VERSION 5.8 ;
BUSBITCHARS "[]" ;
DIVIDERCHAR "/" ;
UNITS
    DATABASE MICRONS 1000 ;
END UNITS

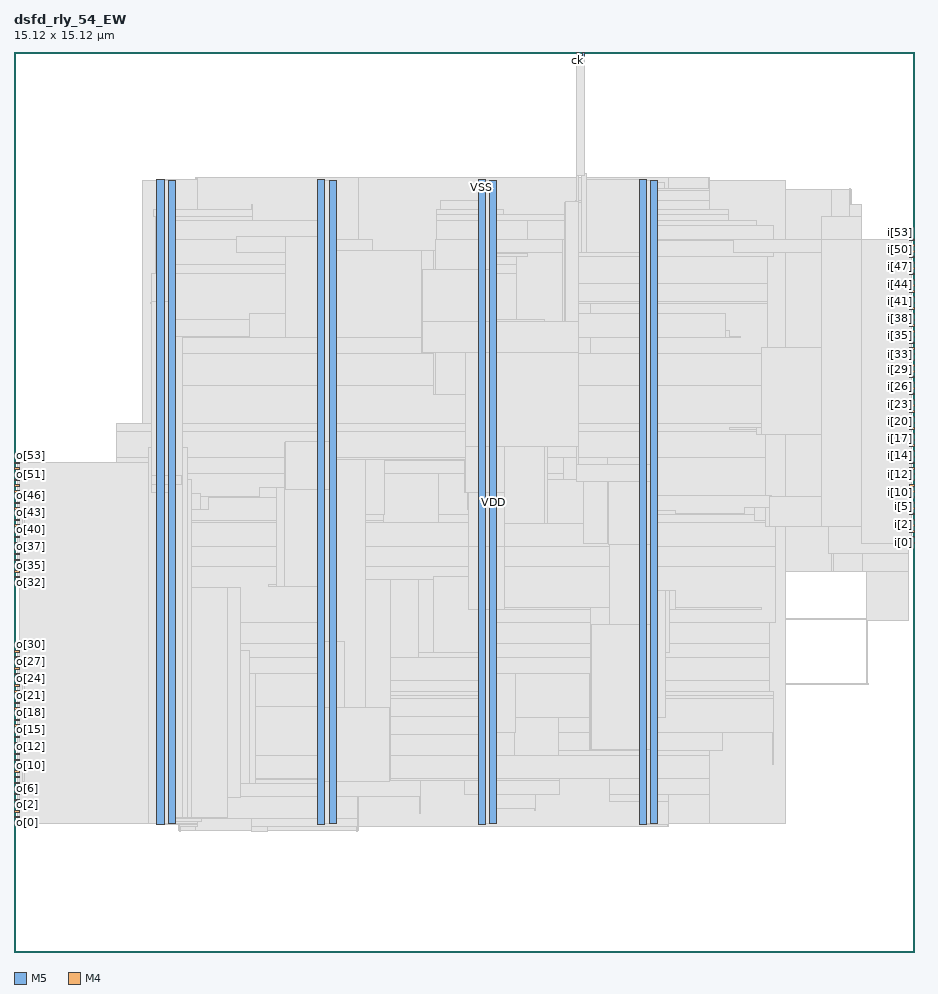
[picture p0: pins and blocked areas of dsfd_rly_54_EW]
MACRO dsfd_rly_54_EW
  FOREIGN dsfd_rly_54_EW 0 0 ;
  CLASS BLOCK ;
  SIZE 15.12 BY 15.12 ;
  PIN ck
    DIRECTION INPUT ;
    USE SIGNAL ;
    PORT
      LAYER M5 ;
        RECT  9.456 15.036 9.48 15.12 ;
    END
  END ck
  PIN i[0]
    DIRECTION INPUT ;
    USE SIGNAL ;
    PORT
      LAYER M4 ;
        RECT  15.036 6.864 15.12 6.888 ;
    END
  END i[0]
  PIN i[10]
    DIRECTION INPUT ;
    USE SIGNAL ;
    PORT
      LAYER M4 ;
        RECT  15.036 7.824 15.12 7.848 ;
    END
  END i[10]
  PIN i[11]
    DIRECTION INPUT ;
    USE SIGNAL ;
    PORT
      LAYER M4 ;
        RECT  15.036 7.92 15.12 7.944 ;
    END
  END i[11]
  PIN i[12]
    DIRECTION INPUT ;
    USE SIGNAL ;
    PORT
      LAYER M4 ;
        RECT  15.036 8.016 15.12 8.04 ;
    END
  END i[12]
  PIN i[13]
    DIRECTION INPUT ;
    USE SIGNAL ;
    PORT
      LAYER M4 ;
        RECT  15.036 8.112 15.12 8.136 ;
    END
  END i[13]
  PIN i[14]
    DIRECTION INPUT ;
    USE SIGNAL ;
    PORT
      LAYER M4 ;
        RECT  15.036 8.208 15.12 8.232 ;
    END
  END i[14]
  PIN i[15]
    DIRECTION INPUT ;
    USE SIGNAL ;
    PORT
      LAYER M4 ;
        RECT  15.036 8.304 15.12 8.328 ;
    END
  END i[15]
  PIN i[16]
    DIRECTION INPUT ;
    USE SIGNAL ;
    PORT
      LAYER M4 ;
        RECT  15.036 8.4 15.12 8.424 ;
    END
  END i[16]
  PIN i[17]
    DIRECTION INPUT ;
    USE SIGNAL ;
    PORT
      LAYER M4 ;
        RECT  15.036 8.496 15.12 8.52 ;
    END
  END i[17]
  PIN i[18]
    DIRECTION INPUT ;
    USE SIGNAL ;
    PORT
      LAYER M4 ;
        RECT  15.036 8.592 15.12 8.616 ;
    END
  END i[18]
  PIN i[19]
    DIRECTION INPUT ;
    USE SIGNAL ;
    PORT
      LAYER M4 ;
        RECT  15.036 8.688 15.12 8.712 ;
    END
  END i[19]
  PIN i[1]
    DIRECTION INPUT ;
    USE SIGNAL ;
    PORT
      LAYER M4 ;
        RECT  15.036 6.96 15.12 6.984 ;
    END
  END i[1]
  PIN i[20]
    DIRECTION INPUT ;
    USE SIGNAL ;
    PORT
      LAYER M4 ;
        RECT  15.036 8.784 15.12 8.808 ;
    END
  END i[20]
  PIN i[21]
    DIRECTION INPUT ;
    USE SIGNAL ;
    PORT
      LAYER M4 ;
        RECT  15.036 8.88 15.12 8.904 ;
    END
  END i[21]
  PIN i[22]
    DIRECTION INPUT ;
    USE SIGNAL ;
    PORT
      LAYER M4 ;
        RECT  15.036 8.976 15.12 9 ;
    END
  END i[22]
  PIN i[23]
    DIRECTION INPUT ;
    USE SIGNAL ;
    PORT
      LAYER M4 ;
        RECT  15.036 9.072 15.12 9.096 ;
    END
  END i[23]
  PIN i[24]
    DIRECTION INPUT ;
    USE SIGNAL ;
    PORT
      LAYER M4 ;
        RECT  15.036 9.168 15.12 9.192 ;
    END
  END i[24]
  PIN i[25]
    DIRECTION INPUT ;
    USE SIGNAL ;
    PORT
      LAYER M4 ;
        RECT  15.036 9.264 15.12 9.288 ;
    END
  END i[25]
  PIN i[26]
    DIRECTION INPUT ;
    USE SIGNAL ;
    PORT
      LAYER M4 ;
        RECT  15.036 9.36 15.12 9.384 ;
    END
  END i[26]
  PIN i[27]
    DIRECTION INPUT ;
    USE SIGNAL ;
    PORT
      LAYER M4 ;
        RECT  15.036 9.456 15.12 9.48 ;
    END
  END i[27]
  PIN i[28]
    DIRECTION INPUT ;
    USE SIGNAL ;
    PORT
      LAYER M4 ;
        RECT  15.036 9.552 15.12 9.576 ;
    END
  END i[28]
  PIN i[29]
    DIRECTION INPUT ;
    USE SIGNAL ;
    PORT
      LAYER M4 ;
        RECT  15.036 9.648 15.12 9.672 ;
    END
  END i[29]
  PIN i[2]
    DIRECTION INPUT ;
    USE SIGNAL ;
    PORT
      LAYER M4 ;
        RECT  15.036 7.056 15.12 7.08 ;
    END
  END i[2]
  PIN i[30]
    DIRECTION INPUT ;
    USE SIGNAL ;
    PORT
      LAYER M4 ;
        RECT  15.036 9.744 15.12 9.768 ;
    END
  END i[30]
  PIN i[31]
    DIRECTION INPUT ;
    USE SIGNAL ;
    PORT
      LAYER M4 ;
        RECT  15.036 9.84 15.12 9.864 ;
    END
  END i[31]
  PIN i[32]
    DIRECTION INPUT ;
    USE SIGNAL ;
    PORT
      LAYER M4 ;
        RECT  15.036 9.936 15.12 9.96 ;
    END
  END i[32]
  PIN i[33]
    DIRECTION INPUT ;
    USE SIGNAL ;
    PORT
      LAYER M4 ;
        RECT  15.036 10.032 15.12 10.056 ;
    END
  END i[33]
  PIN i[34]
    DIRECTION INPUT ;
    USE SIGNAL ;
    PORT
      LAYER M4 ;
        RECT  15.036 10.128 15.12 10.152 ;
    END
  END i[34]
  PIN i[35]
    DIRECTION INPUT ;
    USE SIGNAL ;
    PORT
      LAYER M4 ;
        RECT  15.036 10.224 15.12 10.248 ;
    END
  END i[35]
  PIN i[36]
    DIRECTION INPUT ;
    USE SIGNAL ;
    PORT
      LAYER M4 ;
        RECT  15.036 10.32 15.12 10.344 ;
    END
  END i[36]
  PIN i[37]
    DIRECTION INPUT ;
    USE SIGNAL ;
    PORT
      LAYER M4 ;
        RECT  15.036 10.416 15.12 10.44 ;
    END
  END i[37]
  PIN i[38]
    DIRECTION INPUT ;
    USE SIGNAL ;
    PORT
      LAYER M4 ;
        RECT  15.036 10.512 15.12 10.536 ;
    END
  END i[38]
  PIN i[39]
    DIRECTION INPUT ;
    USE SIGNAL ;
    PORT
      LAYER M4 ;
        RECT  15.036 10.608 15.12 10.632 ;
    END
  END i[39]
  PIN i[3]
    DIRECTION INPUT ;
    USE SIGNAL ;
    PORT
      LAYER M4 ;
        RECT  15.036 7.152 15.12 7.176 ;
    END
  END i[3]
  PIN i[40]
    DIRECTION INPUT ;
    USE SIGNAL ;
    PORT
      LAYER M4 ;
        RECT  15.036 10.704 15.12 10.728 ;
    END
  END i[40]
  PIN i[41]
    DIRECTION INPUT ;
    USE SIGNAL ;
    PORT
      LAYER M4 ;
        RECT  15.036 10.8 15.12 10.824 ;
    END
  END i[41]
  PIN i[42]
    DIRECTION INPUT ;
    USE SIGNAL ;
    PORT
      LAYER M4 ;
        RECT  15.036 10.896 15.12 10.92 ;
    END
  END i[42]
  PIN i[43]
    DIRECTION INPUT ;
    USE SIGNAL ;
    PORT
      LAYER M4 ;
        RECT  15.036 10.992 15.12 11.016 ;
    END
  END i[43]
  PIN i[44]
    DIRECTION INPUT ;
    USE SIGNAL ;
    PORT
      LAYER M4 ;
        RECT  15.036 11.088 15.12 11.112 ;
    END
  END i[44]
  PIN i[45]
    DIRECTION INPUT ;
    USE SIGNAL ;
    PORT
      LAYER M4 ;
        RECT  15.036 11.184 15.12 11.208 ;
    END
  END i[45]
  PIN i[46]
    DIRECTION INPUT ;
    USE SIGNAL ;
    PORT
      LAYER M4 ;
        RECT  15.036 11.28 15.12 11.304 ;
    END
  END i[46]
  PIN i[47]
    DIRECTION INPUT ;
    USE SIGNAL ;
    PORT
      LAYER M4 ;
        RECT  15.036 11.376 15.12 11.4 ;
    END
  END i[47]
  PIN i[48]
    DIRECTION INPUT ;
    USE SIGNAL ;
    PORT
      LAYER M4 ;
        RECT  15.036 11.472 15.12 11.496 ;
    END
  END i[48]
  PIN i[49]
    DIRECTION INPUT ;
    USE SIGNAL ;
    PORT
      LAYER M4 ;
        RECT  15.036 11.568 15.12 11.592 ;
    END
  END i[49]
  PIN i[4]
    DIRECTION INPUT ;
    USE SIGNAL ;
    PORT
      LAYER M4 ;
        RECT  15.036 7.248 15.12 7.272 ;
    END
  END i[4]
  PIN i[50]
    DIRECTION INPUT ;
    USE SIGNAL ;
    PORT
      LAYER M4 ;
        RECT  15.036 11.664 15.12 11.688 ;
    END
  END i[50]
  PIN i[51]
    DIRECTION INPUT ;
    USE SIGNAL ;
    PORT
      LAYER M4 ;
        RECT  15.036 11.76 15.12 11.784 ;
    END
  END i[51]
  PIN i[52]
    DIRECTION INPUT ;
    USE SIGNAL ;
    PORT
      LAYER M4 ;
        RECT  15.036 11.856 15.12 11.88 ;
    END
  END i[52]
  PIN i[53]
    DIRECTION INPUT ;
    USE SIGNAL ;
    PORT
      LAYER M4 ;
        RECT  15.036 11.952 15.12 11.976 ;
    END
  END i[53]
  PIN i[5]
    DIRECTION INPUT ;
    USE SIGNAL ;
    PORT
      LAYER M4 ;
        RECT  15.036 7.344 15.12 7.368 ;
    END
  END i[5]
  PIN i[6]
    DIRECTION INPUT ;
    USE SIGNAL ;
    PORT
      LAYER M4 ;
        RECT  15.036 7.44 15.12 7.464 ;
    END
  END i[6]
  PIN i[7]
    DIRECTION INPUT ;
    USE SIGNAL ;
    PORT
      LAYER M4 ;
        RECT  15.036 7.536 15.12 7.56 ;
    END
  END i[7]
  PIN i[8]
    DIRECTION INPUT ;
    USE SIGNAL ;
    PORT
      LAYER M4 ;
        RECT  15.036 7.632 15.12 7.656 ;
    END
  END i[8]
  PIN i[9]
    DIRECTION INPUT ;
    USE SIGNAL ;
    PORT
      LAYER M4 ;
        RECT  15.036 7.728 15.12 7.752 ;
    END
  END i[9]
  PIN o[0]
    DIRECTION OUTPUT ;
    USE SIGNAL ;
    PORT
      LAYER M4 ;
        RECT  0 2.16 0.084 2.184 ;
    END
  END o[0]
  PIN o[10]
    DIRECTION OUTPUT ;
    USE SIGNAL ;
    PORT
      LAYER M4 ;
        RECT  0 3.12 0.084 3.144 ;
    END
  END o[10]
  PIN o[11]
    DIRECTION OUTPUT ;
    USE SIGNAL ;
    PORT
      LAYER M4 ;
        RECT  0 3.216 0.084 3.24 ;
    END
  END o[11]
  PIN o[12]
    DIRECTION OUTPUT ;
    USE SIGNAL ;
    PORT
      LAYER M4 ;
        RECT  0 3.312 0.084 3.336 ;
    END
  END o[12]
  PIN o[13]
    DIRECTION OUTPUT ;
    USE SIGNAL ;
    PORT
      LAYER M4 ;
        RECT  0 3.408 0.084 3.432 ;
    END
  END o[13]
  PIN o[14]
    DIRECTION OUTPUT ;
    USE SIGNAL ;
    PORT
      LAYER M4 ;
        RECT  0 3.504 0.084 3.528 ;
    END
  END o[14]
  PIN o[15]
    DIRECTION OUTPUT ;
    USE SIGNAL ;
    PORT
      LAYER M4 ;
        RECT  0 3.6 0.084 3.624 ;
    END
  END o[15]
  PIN o[16]
    DIRECTION OUTPUT ;
    USE SIGNAL ;
    PORT
      LAYER M4 ;
        RECT  0 3.696 0.084 3.72 ;
    END
  END o[16]
  PIN o[17]
    DIRECTION OUTPUT ;
    USE SIGNAL ;
    PORT
      LAYER M4 ;
        RECT  0 3.792 0.084 3.816 ;
    END
  END o[17]
  PIN o[18]
    DIRECTION OUTPUT ;
    USE SIGNAL ;
    PORT
      LAYER M4 ;
        RECT  0 3.888 0.084 3.912 ;
    END
  END o[18]
  PIN o[19]
    DIRECTION OUTPUT ;
    USE SIGNAL ;
    PORT
      LAYER M4 ;
        RECT  0 3.984 0.084 4.008 ;
    END
  END o[19]
  PIN o[1]
    DIRECTION OUTPUT ;
    USE SIGNAL ;
    PORT
      LAYER M4 ;
        RECT  0 2.256 0.084 2.28 ;
    END
  END o[1]
  PIN o[20]
    DIRECTION OUTPUT ;
    USE SIGNAL ;
    PORT
      LAYER M4 ;
        RECT  0 4.08 0.084 4.104 ;
    END
  END o[20]
  PIN o[21]
    DIRECTION OUTPUT ;
    USE SIGNAL ;
    PORT
      LAYER M4 ;
        RECT  0 4.176 0.084 4.2 ;
    END
  END o[21]
  PIN o[22]
    DIRECTION OUTPUT ;
    USE SIGNAL ;
    PORT
      LAYER M4 ;
        RECT  0 4.272 0.084 4.296 ;
    END
  END o[22]
  PIN o[23]
    DIRECTION OUTPUT ;
    USE SIGNAL ;
    PORT
      LAYER M4 ;
        RECT  0 4.368 0.084 4.392 ;
    END
  END o[23]
  PIN o[24]
    DIRECTION OUTPUT ;
    USE SIGNAL ;
    PORT
      LAYER M4 ;
        RECT  0 4.464 0.084 4.488 ;
    END
  END o[24]
  PIN o[25]
    DIRECTION OUTPUT ;
    USE SIGNAL ;
    PORT
      LAYER M4 ;
        RECT  0 4.56 0.084 4.584 ;
    END
  END o[25]
  PIN o[26]
    DIRECTION OUTPUT ;
    USE SIGNAL ;
    PORT
      LAYER M4 ;
        RECT  0 4.656 0.084 4.68 ;
    END
  END o[26]
  PIN o[27]
    DIRECTION OUTPUT ;
    USE SIGNAL ;
    PORT
      LAYER M4 ;
        RECT  0 4.752 0.084 4.776 ;
    END
  END o[27]
  PIN o[28]
    DIRECTION OUTPUT ;
    USE SIGNAL ;
    PORT
      LAYER M4 ;
        RECT  0 4.848 0.084 4.872 ;
    END
  END o[28]
  PIN o[29]
    DIRECTION OUTPUT ;
    USE SIGNAL ;
    PORT
      LAYER M4 ;
        RECT  0 4.944 0.084 4.968 ;
    END
  END o[29]
  PIN o[2]
    DIRECTION OUTPUT ;
    USE SIGNAL ;
    PORT
      LAYER M4 ;
        RECT  0 2.352 0.084 2.376 ;
    END
  END o[2]
  PIN o[30]
    DIRECTION OUTPUT ;
    USE SIGNAL ;
    PORT
      LAYER M4 ;
        RECT  0 5.04 0.084 5.064 ;
    END
  END o[30]
  PIN o[31]
    DIRECTION OUTPUT ;
    USE SIGNAL ;
    PORT
      LAYER M4 ;
        RECT  0 5.136 0.084 5.16 ;
    END
  END o[31]
  PIN o[32]
    DIRECTION OUTPUT ;
    USE SIGNAL ;
    PORT
      LAYER M4 ;
        RECT  0 6.192 0.084 6.216 ;
    END
  END o[32]
  PIN o[33]
    DIRECTION OUTPUT ;
    USE SIGNAL ;
    PORT
      LAYER M4 ;
        RECT  0 6.288 0.084 6.312 ;
    END
  END o[33]
  PIN o[34]
    DIRECTION OUTPUT ;
    USE SIGNAL ;
    PORT
      LAYER M4 ;
        RECT  0 6.384 0.084 6.408 ;
    END
  END o[34]
  PIN o[35]
    DIRECTION OUTPUT ;
    USE SIGNAL ;
    PORT
      LAYER M4 ;
        RECT  0 6.48 0.084 6.504 ;
    END
  END o[35]
  PIN o[36]
    DIRECTION OUTPUT ;
    USE SIGNAL ;
    PORT
      LAYER M4 ;
        RECT  0 6.576 0.084 6.6 ;
    END
  END o[36]
  PIN o[37]
    DIRECTION OUTPUT ;
    USE SIGNAL ;
    PORT
      LAYER M4 ;
        RECT  0 6.672 0.084 6.696 ;
    END
  END o[37]
  PIN o[38]
    DIRECTION OUTPUT ;
    USE SIGNAL ;
    PORT
      LAYER M4 ;
        RECT  0 6.768 0.084 6.792 ;
    END
  END o[38]
  PIN o[39]
    DIRECTION OUTPUT ;
    USE SIGNAL ;
    PORT
      LAYER M4 ;
        RECT  0 6.864 0.084 6.888 ;
    END
  END o[39]
  PIN o[3]
    DIRECTION OUTPUT ;
    USE SIGNAL ;
    PORT
      LAYER M4 ;
        RECT  0 2.448 0.084 2.472 ;
    END
  END o[3]
  PIN o[40]
    DIRECTION OUTPUT ;
    USE SIGNAL ;
    PORT
      LAYER M4 ;
        RECT  0 6.96 0.084 6.984 ;
    END
  END o[40]
  PIN o[41]
    DIRECTION OUTPUT ;
    USE SIGNAL ;
    PORT
      LAYER M4 ;
        RECT  0 7.056 0.084 7.08 ;
    END
  END o[41]
  PIN o[42]
    DIRECTION OUTPUT ;
    USE SIGNAL ;
    PORT
      LAYER M4 ;
        RECT  0 7.152 0.084 7.176 ;
    END
  END o[42]
  PIN o[43]
    DIRECTION OUTPUT ;
    USE SIGNAL ;
    PORT
      LAYER M4 ;
        RECT  0 7.248 0.084 7.272 ;
    END
  END o[43]
  PIN o[44]
    DIRECTION OUTPUT ;
    USE SIGNAL ;
    PORT
      LAYER M4 ;
        RECT  0 7.344 0.084 7.368 ;
    END
  END o[44]
  PIN o[45]
    DIRECTION OUTPUT ;
    USE SIGNAL ;
    PORT
      LAYER M4 ;
        RECT  0 7.44 0.084 7.464 ;
    END
  END o[45]
  PIN o[46]
    DIRECTION OUTPUT ;
    USE SIGNAL ;
    PORT
      LAYER M4 ;
        RECT  0 7.536 0.084 7.56 ;
    END
  END o[46]
  PIN o[47]
    DIRECTION OUTPUT ;
    USE SIGNAL ;
    PORT
      LAYER M4 ;
        RECT  0 7.632 0.084 7.656 ;
    END
  END o[47]
  PIN o[48]
    DIRECTION OUTPUT ;
    USE SIGNAL ;
    PORT
      LAYER M4 ;
        RECT  0 7.728 0.084 7.752 ;
    END
  END o[48]
  PIN o[49]
    DIRECTION OUTPUT ;
    USE SIGNAL ;
    PORT
      LAYER M4 ;
        RECT  0 7.824 0.084 7.848 ;
    END
  END o[49]
  PIN o[4]
    DIRECTION OUTPUT ;
    USE SIGNAL ;
    PORT
      LAYER M4 ;
        RECT  0 2.544 0.084 2.568 ;
    END
  END o[4]
  PIN o[50]
    DIRECTION OUTPUT ;
    USE SIGNAL ;
    PORT
      LAYER M4 ;
        RECT  0 7.92 0.084 7.944 ;
    END
  END o[50]
  PIN o[51]
    DIRECTION OUTPUT ;
    USE SIGNAL ;
    PORT
      LAYER M4 ;
        RECT  0 8.016 0.084 8.04 ;
    END
  END o[51]
  PIN o[52]
    DIRECTION OUTPUT ;
    USE SIGNAL ;
    PORT
      LAYER M4 ;
        RECT  0 8.112 0.084 8.136 ;
    END
  END o[52]
  PIN o[53]
    DIRECTION OUTPUT ;
    USE SIGNAL ;
    PORT
      LAYER M4 ;
        RECT  0 8.208 0.084 8.232 ;
    END
  END o[53]
  PIN o[5]
    DIRECTION OUTPUT ;
    USE SIGNAL ;
    PORT
      LAYER M4 ;
        RECT  0 2.64 0.084 2.664 ;
    END
  END o[5]
  PIN o[6]
    DIRECTION OUTPUT ;
    USE SIGNAL ;
    PORT
      LAYER M4 ;
        RECT  0 2.736 0.084 2.76 ;
    END
  END o[6]
  PIN o[7]
    DIRECTION OUTPUT ;
    USE SIGNAL ;
    PORT
      LAYER M4 ;
        RECT  0 2.832 0.084 2.856 ;
    END
  END o[7]
  PIN o[8]
    DIRECTION OUTPUT ;
    USE SIGNAL ;
    PORT
      LAYER M4 ;
        RECT  0 2.928 0.084 2.952 ;
    END
  END o[8]
  PIN o[9]
    DIRECTION OUTPUT ;
    USE SIGNAL ;
    PORT
      LAYER M4 ;
        RECT  0 3.024 0.084 3.048 ;
    END
  END o[9]
  PIN rs
    DIRECTION INPUT ;
    USE SIGNAL ;
    PORT
      LAYER M5 ;
        RECT  9.552 15.036 9.576 15.12 ;
    END
  END rs
  PIN VDD
    DIRECTION INOUT ;
    USE POWER ;
    PORT
      LAYER M5 ;
        RECT  10.692 2.151 10.812 12.969 ;
        RECT  7.992 2.151 8.112 12.969 ;
        RECT  5.292 2.151 5.412 12.969 ;
        RECT  2.592 2.151 2.712 12.969 ;
    END
  END VDD
  PIN VSS
    DIRECTION INOUT ;
    USE GROUND ;
    PORT
      LAYER M5 ;
        RECT  10.5 2.137 10.62 12.983 ;
        RECT  7.8 2.137 7.92 12.983 ;
        RECT  5.1 2.137 5.22 12.983 ;
        RECT  2.4 2.137 2.52 12.983 ;
    END
  END VSS
  OBS
    LAYER RVTN ;
     RECT  2.16 2.16 12.96 2.295 ;
     RECT  2.16 2.565 12.96 2.835 ;
     RECT  2.16 3.105 12.96 3.375 ;
     RECT  2.16 3.645 12.96 3.915 ;
     RECT  2.16 4.185 12.96 4.455 ;
     RECT  2.16 4.725 12.96 4.995 ;
     RECT  2.16 5.265 12.96 5.535 ;
     RECT  2.16 5.805 12.96 6.075 ;
     RECT  2.16 6.345 12.96 6.615 ;
     RECT  2.16 6.885 12.96 7.155 ;
     RECT  2.16 7.425 12.96 7.695 ;
     RECT  2.16 7.965 12.96 8.235 ;
     RECT  2.16 8.505 12.96 8.775 ;
     RECT  2.16 9.045 12.96 9.315 ;
     RECT  2.16 9.585 12.96 9.855 ;
     RECT  2.16 10.125 12.96 10.395 ;
     RECT  2.16 10.665 12.96 10.935 ;
     RECT  2.16 11.205 12.96 11.475 ;
     RECT  2.16 11.745 12.96 12.015 ;
     RECT  2.16 12.285 12.96 12.555 ;
     RECT  2.16 12.825 12.96 12.96 ;
    LAYER RVTP ;
     RECT  2.16 2.295 12.96 2.565 ;
     RECT  2.16 2.835 12.96 3.105 ;
     RECT  2.16 3.375 12.96 3.645 ;
     RECT  2.16 3.915 12.96 4.185 ;
     RECT  2.16 4.455 12.96 4.725 ;
     RECT  2.16 4.995 12.96 5.265 ;
     RECT  2.16 5.535 12.96 5.805 ;
     RECT  2.16 6.075 12.96 6.345 ;
     RECT  2.16 6.615 12.96 6.885 ;
     RECT  2.16 7.155 12.96 7.425 ;
     RECT  2.16 7.695 12.96 7.965 ;
     RECT  2.16 8.235 12.96 8.505 ;
     RECT  2.16 8.775 12.96 9.045 ;
     RECT  2.16 9.315 12.96 9.585 ;
     RECT  2.16 9.855 12.96 10.125 ;
     RECT  2.16 10.395 12.96 10.665 ;
     RECT  2.16 10.935 12.96 11.205 ;
     RECT  2.16 11.475 12.96 11.745 ;
     RECT  2.16 12.015 12.96 12.285 ;
     RECT  2.16 12.555 12.96 12.825 ;
    LAYER M1 ;
     RECT  2.16 2.151 12.96 12.969 ;
    LAYER M2 ;
     RECT  0.103 3.888 0.203 3.906 ;
     RECT  0.211 5.04 0.347 5.058 ;
     RECT  0.103 7.866 2.16 7.884 ;
     RECT  1.723 8.856 2.16 8.874 ;
     RECT  2.16 2.151 2.767 12.969 ;
     RECT  2.767 2.034 3.055 12.969 ;
     RECT  3.055 2.034 5.783 13.014 ;
     RECT  5.783 2.106 11.003 13.014 ;
     RECT  11.003 2.151 11.687 13.014 ;
     RECT  11.687 2.151 12.96 12.969 ;
     RECT  12.96 6.39 13.739 12.816 ;
     RECT  13.739 6.39 13.775 7.794 ;
     RECT  13.739 9.09 14.063 12.816 ;
     RECT  14.063 9.09 14.171 12.546 ;
     RECT  14.171 9.09 14.243 10.998 ;
     RECT  14.171 11.79 14.243 12.546 ;
     RECT  13.775 6.39 14.279 7.722 ;
     RECT  14.243 9.09 14.279 9.108 ;
     RECT  14.243 10.98 14.279 10.998 ;
     RECT  14.243 11.79 14.279 11.808 ;
     RECT  14.279 6.822 14.315 6.984 ;
     RECT  12.96 4.5 14.351 4.518 ;
     RECT  14.315 6.966 14.387 6.984 ;
     RECT  12.96 5.58 15.035 5.598 ;
     RECT  14.243 9.936 15.035 9.954 ;
    LAYER M3 ;
     RECT  2.772 2.029 2.79 2.101 ;
     RECT  3.996 2.029 4.266 2.101 ;
     RECT  5.76 2.029 5.778 2.101 ;
     RECT  2.772 2.101 3.078 2.143 ;
     RECT  10.98 2.101 10.998 2.143 ;
     RECT  2.415 2.143 3.078 2.155 ;
     RECT  2.304 2.155 3.078 2.191 ;
     RECT  2.304 2.191 3.15 2.251 ;
     RECT  3.996 2.101 5.778 2.251 ;
     RECT  7.815 2.143 7.905 2.413 ;
     RECT  8.748 2.371 8.766 2.413 ;
     RECT  10.515 2.143 10.998 2.533 ;
     RECT  2.304 2.251 5.778 2.605 ;
     RECT  6.804 2.335 6.822 2.605 ;
     RECT  7.815 2.413 8.766 2.641 ;
     RECT  10.008 2.533 10.998 2.641 ;
     RECT  2.304 2.605 6.822 2.875 ;
     RECT  7.56 2.641 9.162 2.875 ;
     RECT  2.304 2.875 9.162 2.911 ;
     RECT  10.008 2.641 11.682 2.911 ;
     RECT  0.144 2.587 0.162 2.923 ;
     RECT  2.304 2.911 11.682 3.299 ;
     RECT  9.144 3.299 11.682 3.379 ;
     RECT  0.144 2.923 0.342 3.629 ;
     RECT  9.144 3.379 11.898 3.685 ;
     RECT  12.744 3.145 12.762 3.685 ;
     RECT  0.144 3.629 0.198 3.868 ;
     RECT  0.108 3.868 0.198 4.109 ;
     RECT  2.304 3.299 8.406 4.261 ;
     RECT  9.144 3.685 12.762 4.261 ;
     RECT  2.268 4.261 12.762 4.301 ;
     RECT  0.144 4.109 0.198 4.363 ;
     RECT  2.304 4.301 12.762 4.379 ;
     RECT  2.304 4.379 12.69 4.559 ;
     RECT  2.34 4.559 12.69 4.955 ;
     RECT  0.144 4.363 0.342 5.069 ;
     RECT  2.376 4.955 12.69 5.189 ;
     RECT  0.108 5.131 0.126 5.261 ;
     RECT  2.415 5.189 12.69 5.539 ;
     RECT  14.328 4.495 14.346 5.575 ;
     RECT  0.108 6.091 0.126 6.221 ;
     RECT  14.328 5.575 15.03 6.385 ;
     RECT  2.415 5.539 12.798 6.475 ;
     RECT  14.256 6.385 15.03 6.691 ;
     RECT  0.144 6.619 0.162 6.797 ;
     RECT  2.304 6.475 12.798 6.817 ;
     RECT  0.324 7.051 0.342 7.181 ;
     RECT  2.232 6.817 12.798 7.223 ;
     RECT  2.232 7.223 6.21 7.243 ;
     RECT  7.128 7.223 12.798 7.349 ;
     RECT  13.68 6.691 15.03 7.565 ;
     RECT  9.972 7.349 12.726 7.661 ;
     RECT  13.68 7.565 14.382 7.757 ;
     RECT  13.68 7.757 14.274 7.915 ;
     RECT  1.728 7.243 6.21 8.041 ;
     RECT  7.128 7.349 9.234 8.041 ;
     RECT  0.108 7.861 0.126 8.141 ;
     RECT  13.608 7.915 14.274 8.203 ;
     RECT  13.572 8.203 14.274 8.303 ;
     RECT  1.728 8.041 9.234 8.311 ;
     RECT  9.972 7.661 12.618 8.311 ;
     RECT  1.728 8.311 12.618 8.743 ;
     RECT  1.728 8.743 12.762 8.879 ;
     RECT  13.644 8.303 14.274 9.197 ;
     RECT  13.644 9.197 14.238 9.259 ;
     RECT  2.304 8.879 12.762 9.509 ;
     RECT  15.012 9.931 15.03 9.968 ;
     RECT  2.304 9.509 12.654 10.049 ;
     RECT  2.304 10.049 8.91 10.625 ;
     RECT  13.608 9.259 14.238 10.699 ;
     RECT  13.572 10.699 14.238 10.795 ;
     RECT  9.684 10.049 12.654 10.891 ;
     RECT  9.252 10.891 12.654 10.931 ;
     RECT  13.572 10.795 14.274 11.003 ;
     RECT  9.396 10.931 12.654 11.237 ;
     RECT  2.304 10.625 8.442 11.399 ;
     RECT  2.376 11.399 8.442 11.543 ;
     RECT  6.984 11.543 8.442 11.677 ;
     RECT  9.432 11.237 12.654 11.677 ;
     RECT  6.984 11.677 8.622 11.741 ;
     RECT  13.572 11.003 14.238 11.785 ;
     RECT  13.572 11.785 14.274 11.885 ;
     RECT  2.376 11.543 6.03 11.975 ;
     RECT  9.432 11.677 12.762 12.209 ;
     RECT  2.376 11.975 5.397 12.281 ;
     RECT  9.432 12.209 12.474 12.281 ;
     RECT  7.092 11.741 8.622 12.289 ;
     RECT  9.432 12.281 12.006 12.289 ;
     RECT  13.572 11.885 14.238 12.353 ;
     RECT  2.376 12.281 4.014 12.361 ;
     RECT  7.092 12.289 12.006 12.389 ;
     RECT  2.34 12.361 4.014 12.479 ;
     RECT  7.092 12.389 8.226 12.479 ;
     RECT  9.432 12.389 12.006 12.479 ;
     RECT  3.996 12.479 4.014 12.551 ;
     RECT  14.04 12.353 14.238 12.551 ;
     RECT  7.164 12.479 8.097 12.623 ;
     RECT  9.432 12.479 11.682 12.623 ;
     RECT  5.115 12.281 5.397 12.707 ;
     RECT  7.815 12.623 8.097 12.707 ;
     RECT  9.54 12.623 9.666 12.749 ;
     RECT  10.404 12.623 11.682 12.785 ;
     RECT  10.515 12.785 11.682 12.821 ;
     RECT  14.04 12.551 14.058 12.821 ;
     RECT  10.515 12.821 10.926 12.929 ;
     RECT  2.415 12.479 3.078 12.977 ;
     RECT  5.115 12.707 5.205 12.977 ;
     RECT  7.815 12.707 7.905 12.977 ;
     RECT  10.515 12.929 10.605 12.977 ;
     RECT  3.06 12.977 3.078 13.019 ;
     RECT  11.664 12.821 11.682 13.019 ;
     RECT  9.54 12.749 9.558 13.085 ;
    LAYER M4 ;
     RECT  0.06 2.16 0.097 5.16 ;
     RECT  0.06 6.192 0.097 8.232 ;
     RECT  0.097 2.16 2.257 8.232 ;
     RECT  2.257 2.16 2.408 8.472 ;
     RECT  2.293 10.896 2.408 10.92 ;
     RECT  2.408 2.148 2.512 12.972 ;
     RECT  2.512 2.256 2.704 12.702 ;
     RECT  2.704 2.256 2.837 10.344 ;
     RECT  2.837 2.256 2.909 8.472 ;
     RECT  2.909 2.256 2.981 7.944 ;
     RECT  2.981 7.44 3.125 7.704 ;
     RECT  3.125 7.44 3.269 7.656 ;
     RECT  2.981 2.256 3.593 6.12 ;
     RECT  3.593 2.592 3.809 6.12 ;
     RECT  2.837 10.32 3.949 10.344 ;
     RECT  3.809 2.832 3.953 5.064 ;
     RECT  3.953 2.832 4.061 4.68 ;
     RECT  3.269 7.632 4.129 7.656 ;
     RECT  4.273 6.144 4.417 6.168 ;
     RECT  4.129 7.632 4.417 7.8 ;
     RECT  4.417 6.144 4.549 7.8 ;
     RECT  3.949 10.32 4.561 10.728 ;
     RECT  3.733 11.76 4.561 12.024 ;
     RECT  4.061 2.832 5.108 2.904 ;
     RECT  4.061 4.128 5.108 4.68 ;
     RECT  4.549 6.144 5.108 8.568 ;
     RECT  4.561 10.32 5.108 12.024 ;
     RECT  5.108 2.148 5.212 12.972 ;
     RECT  5.212 2.418 5.404 12.702 ;
     RECT  5.404 2.88 5.897 8.28 ;
     RECT  5.897 7.344 6.221 8.28 ;
     RECT  5.897 2.88 6.323 6.264 ;
     RECT  6.323 2.88 6.329 3.96 ;
     RECT  6.323 4.944 6.797 6.264 ;
     RECT  5.404 10.32 6.853 11.784 ;
     RECT  6.797 5.04 7.045 6.264 ;
     RECT  6.853 10.08 7.045 11.784 ;
     RECT  7.045 9.36 7.081 11.784 ;
     RECT  6.221 8.256 7.573 8.28 ;
     RECT  7.573 7.728 7.621 8.28 ;
     RECT  6.329 3.648 7.808 3.96 ;
     RECT  7.045 5.04 7.808 6.312 ;
     RECT  7.621 7.44 7.808 8.28 ;
     RECT  7.081 9.36 7.808 11.976 ;
     RECT  7.808 2.148 7.912 12.972 ;
     RECT  7.912 2.418 8.104 12.702 ;
     RECT  8.104 5.76 8.237 10.584 ;
     RECT  8.237 6.816 8.243 10.584 ;
     RECT  8.104 3.696 8.417 4.68 ;
     RECT  8.243 7.2 8.915 10.584 ;
     RECT  8.915 7.2 8.957 8.52 ;
     RECT  8.915 9.648 8.993 10.584 ;
     RECT  8.993 9.888 9.212 10.584 ;
     RECT  8.104 11.76 9.212 11.976 ;
     RECT  9.212 9.888 9.253 11.976 ;
     RECT  9.253 9.888 9.281 12.6 ;
     RECT  9.281 10.32 9.299 12.6 ;
     RECT  9.299 11.76 9.529 12.6 ;
     RECT  8.957 7.2 9.565 7.944 ;
     RECT  9.529 11.76 9.613 13.08 ;
     RECT  8.417 3.936 9.673 4.68 ;
     RECT  9.673 3.408 9.685 4.68 ;
     RECT  8.237 5.76 9.685 5.784 ;
     RECT  9.565 6.864 9.973 7.944 ;
     RECT  9.685 3.408 9.997 5.784 ;
     RECT  9.973 6.864 9.997 8.184 ;
     RECT  9.997 3.408 10.508 8.184 ;
     RECT  9.299 10.32 10.508 10.728 ;
     RECT  9.613 11.76 10.508 12.972 ;
     RECT  10.508 2.148 10.612 12.972 ;
     RECT  10.612 2.418 10.804 12.702 ;
     RECT  10.804 3.936 10.937 6.072 ;
     RECT  10.937 5.04 11.009 6.072 ;
     RECT  11.009 5.76 11.117 6.072 ;
     RECT  10.804 7.344 11.117 7.416 ;
     RECT  10.804 10.32 11.945 10.728 ;
     RECT  11.945 10.32 12.017 10.44 ;
     RECT  10.804 11.952 12.085 11.976 ;
     RECT  12.017 10.32 12.197 10.344 ;
     RECT  11.117 7.344 12.265 7.368 ;
     RECT  12.265 7.344 12.445 7.464 ;
     RECT  12.013 8.784 12.481 8.808 ;
     RECT  12.481 8.688 12.553 8.808 ;
     RECT  11.117 5.76 12.557 5.784 ;
     RECT  12.445 7.248 12.625 7.464 ;
     RECT  12.625 7.152 12.697 7.464 ;
     RECT  12.697 7.152 13.561 7.656 ;
     RECT  12.553 8.688 13.561 10.152 ;
     RECT  12.085 11.76 13.561 11.976 ;
     RECT  13.561 7.152 14.245 11.976 ;
     RECT  14.245 6.864 15.084 11.976 ;
    LAYER M5 ;
     RECT  2.4 2.137 2.52 2.151 ;
     RECT  5.1 2.137 5.22 2.151 ;
     RECT  7.8 2.137 7.92 2.151 ;
     RECT  10.5 2.137 10.62 2.151 ;
     RECT  5.1 2.151 5.412 2.869 ;
     RECT  0.144 2.869 0.168 3.059 ;
     RECT  10.5 2.151 10.812 3.397 ;
     RECT  5.1 2.869 6.312 4.115 ;
     RECT  0.144 4.213 0.168 4.499 ;
     RECT  5.1 4.115 5.544 5.219 ;
     RECT  9.696 3.397 10.812 5.507 ;
     RECT  7.8 2.151 8.112 5.749 ;
     RECT  7.632 5.749 8.112 6.805 ;
     RECT  10.5 5.507 10.812 6.853 ;
     RECT  0.144 7.141 0.168 7.427 ;
     RECT  2.4 2.151 2.712 7.717 ;
     RECT  7.632 6.805 8.232 7.717 ;
     RECT  5.1 5.219 5.412 7.765 ;
     RECT  2.304 7.717 2.712 7.861 ;
     RECT  9.984 6.853 10.812 7.909 ;
     RECT  2.304 7.861 2.808 8.003 ;
     RECT  9.456 7.909 10.812 8.195 ;
     RECT  7.584 7.717 8.232 8.485 ;
     RECT  9.456 8.195 9.48 8.485 ;
     RECT  4.56 7.765 5.412 8.579 ;
     RECT  7.584 8.485 9.48 10.069 ;
     RECT  6.864 10.069 9.48 10.595 ;
     RECT  2.304 8.003 2.712 10.931 ;
     RECT  6.864 10.595 8.112 11.459 ;
     RECT  9.264 10.595 9.48 12.611 ;
     RECT  2.4 10.931 2.712 12.969 ;
     RECT  5.1 8.579 5.412 12.969 ;
     RECT  7.8 11.459 8.112 12.969 ;
     RECT  10.5 8.195 10.812 12.969 ;
     RECT  2.4 12.969 2.52 12.983 ;
     RECT  5.1 12.969 5.22 12.983 ;
     RECT  7.8 12.969 7.92 12.983 ;
     RECT  10.5 12.969 10.62 12.983 ;
     RECT  9.456 12.611 9.48 13.045 ;
     RECT  9.456 13.045 9.576 15.056 ;
  END
END dsfd_rly_54_EW
END LIBRARY
